# cmos_to_cml : LEF d'integration de MSPHY5973 (prompt-063-leo, 29/09/2026). PIN du LEF source cmos_to_cml.lef,
# OBS recalculees depuis le metal reel du GDS (Metal1 a Metal5, vias compris), moins les PIN de la meme couche.
VERSION 5.7 ;
  NOWIREEXTENSIONATPIN ON ;
  DIVIDERCHAR "/" ;
  BUSBITCHARS "[]" ;
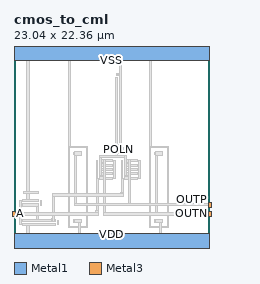
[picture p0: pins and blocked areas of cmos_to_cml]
MACRO cmos_to_cml
  CLASS BLOCK ;
  FOREIGN cmos_to_cml ;
  ORIGIN 0.000 0.000 ;
  SIZE 23.040 BY 22.360 ;
  PIN VDD
    DIRECTION INOUT ;
    USE POWER ;
    PORT
      LAYER Metal1 ;
        RECT 0.000 -1.000 23.040 1.000 ;
    END
  END VDD
  PIN VSS
    DIRECTION INOUT ;
    USE GROUND ;
    PORT
      LAYER Metal1 ;
        RECT 0.000 21.360 23.040 23.360 ;
    END
  END VSS
  PIN A
    DIRECTION INPUT ;
    USE SIGNAL ;
    ANTENNAGATEAREA 1.612000 ;
    PORT
      LAYER Metal3 ;
        RECT -0.150 3.000 0.150 3.600 ;
    END
  END A
  PIN OUTN
    DIRECTION OUTPUT ;
    USE SIGNAL ;
    ANTENNADIFFAREA 1.696000 ;
    PORT
      LAYER Metal3 ;
        RECT 22.890 3.000 23.190 3.600 ;
    END
  END OUTN
  PIN OUTP
    DIRECTION OUTPUT ;
    USE SIGNAL ;
    ANTENNADIFFAREA 1.696000 ;
    PORT
      LAYER Metal3 ;
        RECT 22.890 4.100 23.190 4.700 ;
    END
  END OUTP
  PIN POLN
    DIRECTION INPUT ;
    USE SIGNAL ;
    ANTENNAGATEAREA 1.114100 ;
    PORT
      LAYER Metal3 ;
        RECT 12.130 10.400 12.430 11.480 ;
    END
  END POLN
  OBS
    LAYER Metal1 ;
      RECT 1.040 1.930 4.900 2.190 ;
      RECT 1.500 1.000 1.800 1.930 ;
      RECT 5.090 2.060 5.290 2.570 ;
      RECT 7.040 2.340 8.000 2.655 ;
      RECT 16.560 2.340 17.520 2.655 ;
      RECT 1.040 2.440 4.440 2.700 ;
      RECT 4.780 2.440 4.900 2.700 ;
      RECT 4.440 2.410 4.780 2.730 ;
      RECT 1.040 4.220 2.900 4.480 ;
      RECT 2.600 2.700 2.860 4.220 ;
      RECT 0.640 2.060 0.860 4.860 ;
      RECT 3.090 4.350 3.290 4.860 ;
      RECT 10.740 7.380 11.540 7.640 ;
      RECT 10.080 7.350 10.740 7.670 ;
      RECT 13.680 7.380 14.480 7.640 ;
      RECT 13.020 7.350 13.680 7.670 ;
      RECT 10.740 7.890 11.540 8.150 ;
      RECT 10.080 7.860 10.740 8.180 ;
      RECT 13.680 7.890 14.480 8.150 ;
      RECT 13.020 7.860 13.680 8.180 ;
      RECT 10.740 8.400 11.540 8.660 ;
      RECT 10.080 8.370 10.740 8.690 ;
      RECT 13.680 8.400 14.480 8.660 ;
      RECT 13.020 8.370 13.680 8.690 ;
      RECT 10.740 8.910 11.540 9.170 ;
      RECT 10.080 8.880 10.740 9.200 ;
      RECT 13.680 8.910 14.480 9.170 ;
      RECT 13.020 8.880 13.680 9.200 ;
      RECT 9.710 7.530 9.870 9.550 ;
      RECT 9.680 3.150 9.900 7.530 ;
      RECT 11.750 7.510 11.910 9.550 ;
      RECT 12.650 7.530 12.810 9.550 ;
      RECT 12.620 5.350 12.840 7.530 ;
      RECT 14.690 7.510 14.850 9.550 ;
      RECT 10.740 9.420 11.540 9.680 ;
      RECT 10.080 9.390 10.740 9.710 ;
      RECT 13.680 9.420 14.480 9.680 ;
      RECT 13.020 9.390 13.680 9.710 ;
      RECT 7.040 10.265 8.000 10.580 ;
      RECT 16.560 10.265 17.520 10.580 ;
      RECT 12.030 10.570 12.070 10.730 ;
      RECT 12.070 10.540 12.880 10.760 ;
      RECT 11.900 10.940 12.160 19.370 ;
      RECT 12.410 10.940 12.670 19.370 ;
      RECT 12.070 19.740 12.500 19.820 ;
      RECT 12.030 19.580 12.540 19.740 ;
      RECT 12.070 19.550 12.500 19.580 ;
      RECT 1.040 4.730 2.900 4.990 ;
      RECT 1.500 4.990 1.800 5.650 ;
      RECT 1.150 5.650 2.850 5.950 ;
      RECT 1.500 5.950 1.800 21.360 ;
      RECT 6.380 1.840 6.540 11.080 ;
      RECT 6.400 11.240 6.700 21.360 ;
      RECT 6.380 11.080 8.660 11.240 ;
      RECT 8.500 1.840 8.660 11.080 ;
      RECT 6.380 1.680 8.660 1.840 ;
      RECT 15.900 1.840 16.060 11.080 ;
      RECT 15.920 11.240 16.220 21.360 ;
      RECT 15.900 11.080 18.180 11.240 ;
      RECT 18.020 1.840 18.180 11.080 ;
      RECT 15.900 1.680 18.180 1.840 ;
    LAYER Via1 ;
      RECT 7.615 0.005 7.805 0.195 ;
      RECT 17.135 0.005 17.325 0.195 ;
      RECT 7.220 2.415 7.410 2.605 ;
      RECT 7.630 2.415 7.820 2.605 ;
      RECT 16.740 2.415 16.930 2.605 ;
      RECT 17.150 2.415 17.340 2.605 ;
      RECT 4.515 2.475 4.705 2.665 ;
      RECT 0.655 3.205 0.845 3.395 ;
      RECT 9.695 3.205 9.885 3.395 ;
      RECT 12.635 5.405 12.825 5.595 ;
      RECT 10.535 7.415 10.725 7.605 ;
      RECT 13.475 7.415 13.665 7.605 ;
      RECT 10.095 7.925 10.285 8.115 ;
      RECT 13.035 7.925 13.225 8.115 ;
      RECT 10.535 8.435 10.725 8.625 ;
      RECT 13.475 8.435 13.665 8.625 ;
      RECT 10.095 8.945 10.285 9.135 ;
      RECT 13.035 8.945 13.225 9.135 ;
      RECT 10.535 9.455 10.725 9.645 ;
      RECT 13.475 9.455 13.665 9.645 ;
      RECT 7.220 10.315 7.410 10.505 ;
      RECT 7.630 10.315 7.820 10.505 ;
      RECT 16.740 10.315 16.930 10.505 ;
      RECT 17.150 10.315 17.340 10.505 ;
      RECT 12.615 10.555 12.805 10.745 ;
      RECT 11.935 11.165 12.125 11.355 ;
      RECT 11.935 11.575 12.125 11.765 ;
      RECT 12.445 11.575 12.635 11.765 ;
      RECT 11.935 11.985 12.125 12.175 ;
      RECT 12.445 11.985 12.635 12.175 ;
      RECT 11.935 12.395 12.125 12.585 ;
      RECT 12.445 12.395 12.635 12.585 ;
      RECT 11.935 12.805 12.125 12.995 ;
      RECT 12.445 12.805 12.635 12.995 ;
      RECT 11.935 13.215 12.125 13.405 ;
      RECT 12.445 13.215 12.635 13.405 ;
      RECT 11.935 13.625 12.125 13.815 ;
      RECT 12.445 13.625 12.635 13.815 ;
      RECT 11.935 14.035 12.125 14.225 ;
      RECT 12.445 14.035 12.635 14.225 ;
      RECT 11.935 14.445 12.125 14.635 ;
      RECT 12.445 14.445 12.635 14.635 ;
      RECT 11.935 14.855 12.125 15.045 ;
      RECT 12.445 14.855 12.635 15.045 ;
      RECT 11.935 15.265 12.125 15.455 ;
      RECT 12.445 15.265 12.635 15.455 ;
      RECT 11.935 15.675 12.125 15.865 ;
      RECT 12.445 15.675 12.635 15.865 ;
      RECT 11.935 16.085 12.125 16.275 ;
      RECT 12.445 16.085 12.635 16.275 ;
      RECT 11.935 16.495 12.125 16.685 ;
      RECT 12.445 16.495 12.635 16.685 ;
      RECT 11.935 16.905 12.125 17.095 ;
      RECT 12.445 16.905 12.635 17.095 ;
      RECT 11.935 17.315 12.125 17.505 ;
      RECT 12.445 17.315 12.635 17.505 ;
      RECT 11.935 17.725 12.125 17.915 ;
      RECT 12.445 17.725 12.635 17.915 ;
      RECT 11.935 18.135 12.125 18.325 ;
      RECT 12.445 18.135 12.635 18.325 ;
      RECT 11.935 18.545 12.125 18.735 ;
      RECT 12.445 18.545 12.635 18.735 ;
      RECT 11.935 18.955 12.125 19.145 ;
      RECT 12.445 18.955 12.635 19.145 ;
      RECT 12.445 21.415 12.635 21.605 ;
    LAYER Metal2 ;
      RECT 7.090 2.325 7.950 2.695 ;
      RECT 7.600 -0.050 7.820 2.325 ;
      RECT 16.610 2.325 17.470 2.695 ;
      RECT 17.120 -0.050 17.340 2.325 ;
      RECT 0.600 3.150 0.900 3.650 ;
      RECT 9.630 3.150 9.940 3.650 ;
      RECT 4.500 2.420 4.720 5.700 ;
      RECT 12.570 5.350 12.880 5.850 ;
      RECT 10.520 3.150 10.740 9.730 ;
      RECT 13.460 4.250 13.680 9.730 ;
      RECT 7.100 4.250 7.320 10.225 ;
      RECT 7.090 10.225 7.950 10.595 ;
      RECT 16.620 3.150 16.840 10.225 ;
      RECT 16.610 10.225 17.470 10.595 ;
      RECT 12.580 10.400 12.900 10.850 ;
      RECT 10.080 7.840 10.300 9.950 ;
      RECT 11.920 10.170 12.140 19.330 ;
      RECT 10.080 9.950 13.020 10.170 ;
      RECT 13.020 7.840 13.240 10.170 ;
      RECT 12.430 11.300 12.650 21.660 ;
    LAYER Via2 ;
      RECT 0.655 3.205 0.845 3.395 ;
      RECT 9.695 3.205 9.885 3.395 ;
      RECT 10.535 3.205 10.725 3.395 ;
      RECT 16.635 3.205 16.825 3.395 ;
      RECT 7.115 4.305 7.305 4.495 ;
      RECT 13.475 4.305 13.665 4.495 ;
      RECT 4.515 5.405 4.705 5.595 ;
      RECT 12.635 5.405 12.825 5.595 ;
      RECT 12.615 10.555 12.805 10.745 ;
    LAYER Metal3 ;
      RECT 0.150 3.150 9.940 3.450 ;
      RECT 10.520 3.150 22.890 3.450 ;
      RECT 7.100 4.250 22.890 4.550 ;
      RECT 4.500 5.350 12.880 5.650 ;
      RECT 12.430 10.400 12.900 11.180 ;
  END
END cmos_to_cml
END LIBRARY

